VERSION 5.7 ;
  NOWIREEXTENSIONATPIN ON ;
  DIVIDERCHAR "/" ;
  BUSBITCHARS "[]" ;
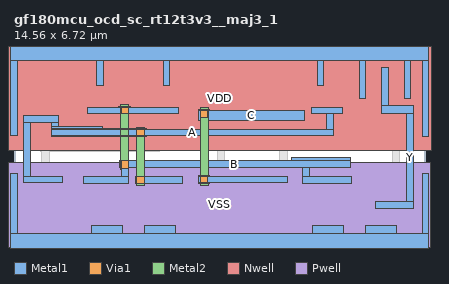
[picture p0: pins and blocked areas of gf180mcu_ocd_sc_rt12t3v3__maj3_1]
MACRO gf180mcu_ocd_sc_rt12t3v3__maj3_1
  CLASS CORE ;
  FOREIGN gf180mcu_ocd_sc_rt12t3v3__maj3_1 ;
  ORIGIN 0.000 0.000 ;
  SIZE 14.560 BY 6.720 ;
  SYMMETRY X Y ;
  SITE unithd ;
  PIN A
    DIRECTION INPUT ;
    USE SIGNAL ;
    ANTENNAGATEAREA 3.344600 ;
    PORT
      LAYER Metal1 ;
        RECT 10.515 4.540 11.615 4.770 ;
        RECT 0.345 4.240 1.565 4.470 ;
        RECT 0.345 2.325 0.575 4.240 ;
        RECT 1.335 4.095 1.565 4.240 ;
        RECT 1.335 4.000 3.145 4.095 ;
        RECT 1.335 3.990 4.690 4.000 ;
        RECT 11.065 3.990 11.295 4.540 ;
        RECT 1.335 3.760 11.295 3.990 ;
        RECT 1.335 3.740 4.690 3.760 ;
        RECT 1.335 3.735 3.145 3.740 ;
        RECT 0.345 2.095 1.700 2.325 ;
        RECT 4.290 2.320 4.670 2.325 ;
        RECT 4.290 2.075 5.975 2.320 ;
        RECT 4.290 2.065 4.670 2.075 ;
      LAYER Via1 ;
        RECT 4.350 3.740 4.610 4.000 ;
        RECT 4.350 2.065 4.610 2.325 ;
      LAYER Metal2 ;
        RECT 4.340 2.005 4.620 4.060 ;
    END
  END A
  PIN B
    DIRECTION INPUT ;
    USE SIGNAL ;
    ANTENNAGATEAREA 3.344600 ;
    PORT
      LAYER Metal1 ;
        RECT 3.705 4.770 4.110 4.800 ;
        RECT 2.610 4.540 5.830 4.770 ;
        RECT 9.810 2.875 11.895 2.980 ;
        RECT 3.730 2.620 11.895 2.875 ;
        RECT 3.790 2.320 4.050 2.620 ;
        RECT 2.465 2.075 4.050 2.320 ;
        RECT 10.215 2.320 10.445 2.620 ;
        RECT 10.215 2.075 11.935 2.320 ;
        RECT 10.215 2.070 10.445 2.075 ;
      LAYER Via1 ;
        RECT 3.790 4.540 4.050 4.800 ;
        RECT 3.790 2.615 4.050 2.875 ;
      LAYER Metal2 ;
        RECT 3.780 2.555 4.060 4.860 ;
    END
  END B
  PIN C
    DIRECTION INPUT ;
    USE SIGNAL ;
    ANTENNAGATEAREA 3.344600 ;
    PORT
      LAYER Metal1 ;
        RECT 6.520 4.660 6.920 4.670 ;
        RECT 6.520 4.300 10.265 4.660 ;
        RECT 6.520 2.325 6.920 2.340 ;
        RECT 6.520 2.095 9.675 2.325 ;
        RECT 6.520 2.080 6.920 2.095 ;
      LAYER Via1 ;
        RECT 6.600 4.410 6.860 4.670 ;
        RECT 6.600 2.080 6.860 2.340 ;
      LAYER Metal2 ;
        RECT 6.590 2.000 6.870 4.740 ;
    END
  END C
  PIN Y
    DIRECTION OUTPUT ;
    USE SIGNAL ;
    ANTENNADIFFAREA 0.976900 ;
    PORT
      LAYER Metal1 ;
        RECT 13.005 4.820 13.235 6.180 ;
        RECT 13.005 4.560 14.130 4.820 ;
        RECT 13.870 1.425 14.130 4.560 ;
        RECT 12.780 1.195 14.130 1.425 ;
    END
  END Y
  PIN VDD
    DIRECTION INOUT ;
    USE POWER ;
    SHAPE ABUTMENT ;
    PORT
      LAYER Nwell ;
        RECT -0.660 3.245 15.120 7.330 ;
      LAYER Metal1 ;
        RECT -0.115 6.420 14.675 7.020 ;
        RECT -0.115 3.750 0.115 6.420 ;
        RECT 2.925 5.520 3.155 6.420 ;
        RECT 5.285 5.520 5.515 6.420 ;
        RECT 10.725 5.520 10.955 6.420 ;
        RECT 12.205 5.065 12.435 6.420 ;
        RECT 13.805 5.060 14.035 6.420 ;
        RECT 14.445 3.745 14.675 6.420 ;
    END
  END VDD
  PIN VSS
    DIRECTION INOUT ;
    USE GROUND ;
    SHAPE ABUTMENT ;
    PORT
      LAYER Pwell ;
        RECT -0.180 -0.180 14.740 2.815 ;
      LAYER Metal1 ;
        RECT -0.115 0.300 0.115 2.410 ;
        RECT 2.730 0.300 3.840 0.585 ;
        RECT 4.600 0.300 5.710 0.585 ;
        RECT 10.550 0.300 11.660 0.585 ;
        RECT 12.430 0.300 13.540 0.585 ;
        RECT 14.445 0.300 14.675 2.410 ;
        RECT -0.115 -0.300 14.675 0.300 ;
    END
  END VSS
  OBS
      LAYER Metal1 ;
        RECT 0.525 5.960 2.355 6.190 ;
        RECT 0.525 5.055 0.755 5.960 ;
        RECT 1.315 5.700 1.570 5.730 ;
        RECT 0.990 4.945 1.570 5.700 ;
        RECT 2.125 5.290 2.355 5.960 ;
        RECT 3.725 5.290 3.955 6.190 ;
        RECT 2.125 5.060 3.955 5.290 ;
        RECT 4.485 5.290 4.715 6.190 ;
        RECT 6.085 5.960 7.915 6.190 ;
        RECT 6.085 5.290 6.315 5.960 ;
        RECT 4.485 5.060 6.315 5.290 ;
        RECT 6.870 4.945 7.450 5.730 ;
        RECT 7.685 5.055 7.915 5.960 ;
        RECT 8.325 5.960 10.155 6.190 ;
        RECT 8.325 5.055 8.555 5.960 ;
        RECT 9.125 5.725 9.355 5.730 ;
        RECT 9.125 5.000 9.680 5.725 ;
        RECT 9.925 5.290 10.155 5.960 ;
        RECT 11.525 5.290 11.755 6.190 ;
        RECT 9.925 5.060 11.755 5.290 ;
        RECT 9.125 4.945 9.355 5.000 ;
        RECT 0.990 4.830 1.250 4.945 ;
        RECT 7.190 4.890 7.450 4.945 ;
        RECT 12.590 4.090 13.640 4.320 ;
        RECT 7.030 3.525 7.490 3.530 ;
        RECT 13.380 3.525 13.630 4.090 ;
        RECT 0.920 3.485 4.220 3.490 ;
        RECT 4.785 3.485 13.630 3.525 ;
        RECT 0.920 3.245 13.630 3.485 ;
        RECT 0.920 3.205 5.145 3.245 ;
        RECT 13.380 2.325 13.630 3.245 ;
        RECT 12.470 2.095 13.640 2.325 ;
        RECT 0.990 1.425 1.250 1.600 ;
        RECT 2.060 1.425 2.290 1.815 ;
        RECT 6.150 1.425 6.380 1.815 ;
        RECT 7.190 1.425 7.450 1.600 ;
        RECT 9.390 1.425 9.650 1.665 ;
        RECT 0.990 1.195 1.520 1.425 ;
        RECT 2.060 1.195 3.460 1.425 ;
        RECT 4.980 1.195 6.380 1.425 ;
        RECT 6.920 1.195 7.450 1.425 ;
        RECT 8.965 1.195 9.650 1.425 ;
        RECT 0.990 0.730 1.250 1.195 ;
        RECT 2.060 0.770 2.290 1.195 ;
        RECT 6.150 0.770 6.380 1.195 ;
        RECT 7.190 0.730 7.450 1.195 ;
        RECT 9.390 0.800 9.650 1.195 ;
        RECT 9.880 1.425 10.110 1.815 ;
        RECT 9.880 1.195 11.280 1.425 ;
        RECT 9.880 0.770 10.110 1.195 ;
      LAYER Via1 ;
        RECT 0.990 4.890 1.250 5.640 ;
        RECT 7.190 4.950 7.450 5.670 ;
        RECT 9.390 5.060 9.650 5.665 ;
        RECT 0.990 3.220 1.250 3.480 ;
        RECT 7.190 3.260 7.450 3.520 ;
        RECT 9.390 3.255 9.650 3.515 ;
        RECT 0.990 0.790 1.250 1.540 ;
        RECT 7.190 0.790 7.450 1.540 ;
        RECT 9.390 0.860 9.650 1.605 ;
      LAYER Metal2 ;
        RECT 0.980 0.690 1.260 5.750 ;
        RECT 7.180 0.690 7.460 5.745 ;
        RECT 9.380 0.770 9.660 5.735 ;
  END
END gf180mcu_ocd_sc_rt12t3v3__maj3_1
END LIBRARY

